VERSION 5.7 ;
BUSBITCHARS "[]" ;
# Minimal SRAM macro: CLASS BLOCK, no SITE declaration.
# Spans 40 rows at Nangate45 row height (1.4um).
# getSiteOrientation() returns nullopt for this cell's site (nullptr)
# at any grid position, triggering bad_optional_access in callers
# that use .value() without checking.
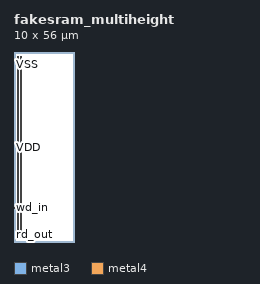
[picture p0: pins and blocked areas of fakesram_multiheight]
MACRO fakesram_multiheight
  FOREIGN fakesram_multiheight 0 0 ;
  SYMMETRY X Y ;
  SIZE 10.000 BY 56.000 ;
  CLASS BLOCK ;
  PIN rd_out
    DIRECTION OUTPUT ;
    USE SIGNAL ;
    PORT
      LAYER metal3 ;
      RECT 0.000 1.000 0.070 1.070 ;
    END
  END rd_out
  PIN wd_in
    DIRECTION INPUT ;
    USE SIGNAL ;
    PORT
      LAYER metal3 ;
      RECT 0.000 10.000 0.070 10.070 ;
    END
  END wd_in
  PIN VDD
    DIRECTION INOUT ;
    USE POWER ;
    PORT
      LAYER metal4 ;
      RECT 2.000 1.400 2.280 54.600 ;
    END
  END VDD
  PIN VSS
    DIRECTION INOUT ;
    USE GROUND ;
    PORT
      LAYER metal4 ;
      RECT 1.000 1.400 1.280 54.600 ;
    END
  END VSS
END fakesram_multiheight

END LIBRARY
